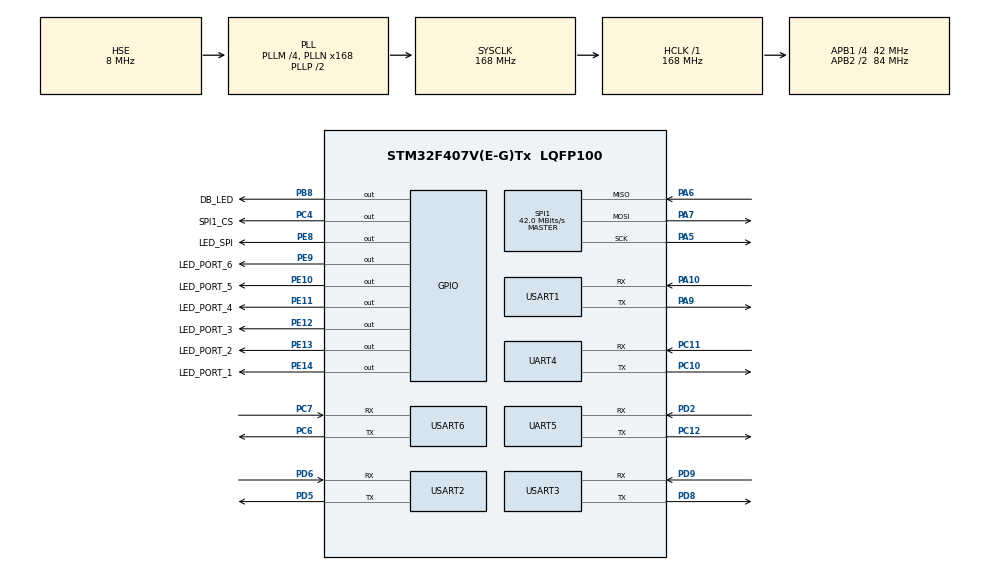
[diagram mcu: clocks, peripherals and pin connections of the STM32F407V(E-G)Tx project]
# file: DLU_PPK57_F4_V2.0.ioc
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Dma.Request0=SPI1_TX
Dma.Request1=UART4_RX
Dma.Request2=UART5_RX
Dma.Request3=USART1_RX
Dma.Request4=USART2_RX
Dma.Request5=USART3_RX
Dma.Request6=USART6_RX
Dma.SPI1_TX.0.Direction=DMA_MEMORY_TO_PERIPH
Dma.SPI1_TX.0.FIFOMode=DMA_FIFOMODE_DISABLE
Dma.SPI1_TX.0.Instance=DMA2_Stream3
Dma.SPI1_TX.0.MemDataAlignment=DMA_MDATAALIGN_BYTE
Dma.SPI1_TX.0.MemInc=DMA_MINC_ENABLE
Dma.SPI1_TX.0.Mode=DMA_NORMAL
Dma.SPI1_TX.0.PeriphDataAlignment=DMA_PDATAALIGN_BYTE
Dma.SPI1_TX.0.PeriphInc=DMA_PINC_DISABLE
Dma.SPI1_TX.0.Priority=DMA_PRIORITY_HIGH
Dma.UART4_RX.1.Direction=DMA_PERIPH_TO_MEMORY
Dma.UART4_RX.1.FIFOMode=DMA_FIFOMODE_DISABLE
Dma.UART4_RX.1.Instance=DMA1_Stream2
Dma.UART4_RX.1.MemDataAlignment=DMA_MDATAALIGN_BYTE
Dma.UART4_RX.1.MemInc=DMA_MINC_ENABLE
Dma.UART4_RX.1.Mode=DMA_NORMAL
Dma.UART4_RX.1.PeriphDataAlignment=DMA_PDATAALIGN_BYTE
Dma.UART4_RX.1.PeriphInc=DMA_PINC_DISABLE
Dma.UART4_RX.1.Priority=DMA_PRIORITY_VERY_HIGH
Dma.UART5_RX.2.Direction=DMA_PERIPH_TO_MEMORY
Dma.UART5_RX.2.FIFOMode=DMA_FIFOMODE_DISABLE
Dma.UART5_RX.2.Instance=DMA1_Stream0
Dma.UART5_RX.2.MemDataAlignment=DMA_MDATAALIGN_BYTE
Dma.UART5_RX.2.MemInc=DMA_MINC_ENABLE
Dma.UART5_RX.2.Mode=DMA_NORMAL
Dma.UART5_RX.2.PeriphDataAlignment=DMA_PDATAALIGN_BYTE
Dma.UART5_RX.2.PeriphInc=DMA_PINC_DISABLE
Dma.UART5_RX.2.Priority=DMA_PRIORITY_VERY_HIGH
Dma.USART1_RX.3.Direction=DMA_PERIPH_TO_MEMORY
Dma.USART1_RX.3.FIFOMode=DMA_FIFOMODE_DISABLE
Dma.USART1_RX.3.Instance=DMA2_Stream2
Dma.USART1_RX.3.MemDataAlignment=DMA_MDATAALIGN_BYTE
Dma.USART1_RX.3.MemInc=DMA_MINC_ENABLE
Dma.USART1_RX.3.Mode=DMA_NORMAL
Dma.USART1_RX.3.PeriphDataAlignment=DMA_PDATAALIGN_BYTE
Dma.USART1_RX.3.PeriphInc=DMA_PINC_DISABLE
Dma.USART1_RX.3.Priority=DMA_PRIORITY_VERY_HIGH
Dma.USART2_RX.4.Direction=DMA_PERIPH_TO_MEMORY
Dma.USART2_RX.4.FIFOMode=DMA_FIFOMODE_DISABLE
Dma.USART2_RX.4.Instance=DMA1_Stream5
Dma.USART2_RX.4.MemDataAlignment=DMA_MDATAALIGN_BYTE
Dma.USART2_RX.4.MemInc=DMA_MINC_ENABLE
Dma.USART2_RX.4.Mode=DMA_NORMAL
Dma.USART2_RX.4.PeriphDataAlignment=DMA_PDATAALIGN_BYTE
Dma.USART2_RX.4.PeriphInc=DMA_PINC_DISABLE
Dma.USART2_RX.4.Priority=DMA_PRIORITY_VERY_HIGH
Dma.USART3_RX.5.Direction=DMA_PERIPH_TO_MEMORY
Dma.USART3_RX.5.FIFOMode=DMA_FIFOMODE_DISABLE
Dma.USART3_RX.5.Instance=DMA1_Stream1
Dma.USART3_RX.5.MemDataAlignment=DMA_MDATAALIGN_BYTE
Dma.USART3_RX.5.MemInc=DMA_MINC_ENABLE
Dma.USART3_RX.5.Mode=DMA_NORMAL
Dma.USART3_RX.5.PeriphDataAlignment=DMA_PDATAALIGN_BYTE
Dma.USART3_RX.5.PeriphInc=DMA_PINC_DISABLE
Dma.USART3_RX.5.Priority=DMA_PRIORITY_VERY_HIGH
Dma.USART6_RX.6.Direction=DMA_PERIPH_TO_MEMORY
Dma.USART6_RX.6.FIFOMode=DMA_FIFOMODE_DISABLE
Dma.USART6_RX.6.Instance=DMA2_Stream1
Dma.USART6_RX.6.MemDataAlignment=DMA_MDATAALIGN_BYTE
Dma.USART6_RX.6.MemInc=DMA_MINC_ENABLE
Dma.USART6_RX.6.Mode=DMA_NORMAL
Dma.USART6_RX.6.PeriphDataAlignment=DMA_PDATAALIGN_BYTE
Dma.USART6_RX.6.PeriphInc=DMA_PINC_DISABLE
Dma.USART6_RX.6.Priority=DMA_PRIORITY_VERY_HIGH
Mcu.Family=STM32F4
Mcu.Name=STM32F407V(E-G)Tx
Mcu.Package=LQFP100
NVIC.DMA1_Stream0_IRQn=true\:0\:0\:false\:false\:true\:false\:true\:true
NVIC.DMA1_Stream1_IRQn=true\:0\:0\:false\:false\:true\:false\:true\:true
NVIC.DMA1_Stream2_IRQn=true\:0\:0\:false\:false\:true\:false\:true\:true
NVIC.DMA1_Stream5_IRQn=true\:0\:0\:false\:false\:true\:false\:true\:true
NVIC.DMA2_Stream1_IRQn=true\:0\:0\:false\:false\:true\:false\:true\:true
NVIC.DMA2_Stream2_IRQn=true\:0\:0\:false\:false\:true\:false\:true\:true
NVIC.DMA2_Stream3_IRQn=true\:0\:0\:false\:false\:true\:false\:true\:true
NVIC.PriorityGroup=NVIC_PRIORITYGROUP_4
NVIC.UART4_IRQn=true\:0\:0\:false\:false\:true\:true\:true\:true
NVIC.UART5_IRQn=true\:0\:0\:false\:false\:true\:true\:true\:true
NVIC.USART1_IRQn=true\:0\:0\:false\:false\:true\:true\:true\:true
NVIC.USART2_IRQn=true\:0\:0\:false\:false\:true\:true\:true\:true
NVIC.USART3_IRQn=true\:0\:0\:false\:false\:true\:true\:true\:true
NVIC.USART6_IRQn=true\:0\:0\:false\:false\:true\:true\:true\:true
PA10.Mode=Asynchronous
PA10.Signal=USART1_RX
PA13.Mode=Serial_Wire
PA13.Signal=SYS_JTMS-SWDIO
PA14.Mode=Serial_Wire
PA14.Signal=SYS_JTCK-SWCLK
PA5.Mode=Full_Duplex_Master
PA5.Signal=SPI1_SCK
PA6.Mode=Full_Duplex_Master
PA6.Signal=SPI1_MISO
PA7.Mode=Full_Duplex_Master
PA7.Signal=SPI1_MOSI
PA9.Mode=Asynchronous
PA9.Signal=USART1_TX
PB8.GPIO_Label=DB_LED
PB8.GPIO_Speed=GPIO_SPEED_FREQ_VERY_HIGH
PB8.Signal=GPIO_Output
PC10.Mode=Asynchronous
PC10.Signal=UART4_TX
PC11.Mode=Asynchronous
PC11.Signal=UART4_RX
PC12.Mode=Asynchronous
PC12.Signal=UART5_TX
PC4.GPIO_Label=SPI1_CS
PC4.GPIO_Speed=GPIO_SPEED_FREQ_VERY_HIGH
PC4.Signal=GPIO_Output
PC6.Mode=Asynchronous
PC6.Signal=USART6_TX
PC7.Mode=Asynchronous
PC7.Signal=USART6_RX
PD2.Mode=Asynchronous
PD2.Signal=UART5_RX
PD5.Mode=Asynchronous
PD5.Signal=USART2_TX
PD6.Mode=Asynchronous
PD6.Signal=USART2_RX
PD8.Mode=Asynchronous
PD8.Signal=USART3_TX
PD9.Mode=Asynchronous
PD9.Signal=USART3_RX
PE10.GPIO_Label=LED_PORT_5
PE10.GPIO_Speed=GPIO_SPEED_FREQ_VERY_HIGH
PE10.Signal=GPIO_Output
PE11.GPIO_Label=LED_PORT_4
PE11.GPIO_Speed=GPIO_SPEED_FREQ_VERY_HIGH
PE11.Signal=GPIO_Output
PE12.GPIO_Label=LED_PORT_3
PE12.GPIO_Speed=GPIO_SPEED_FREQ_VERY_HIGH
PE12.Signal=GPIO_Output
PE13.GPIO_Label=LED_PORT_2
PE13.GPIO_Speed=GPIO_SPEED_FREQ_VERY_HIGH
PE13.Signal=GPIO_Output
PE14.GPIO_Label=LED_PORT_1
PE14.GPIO_Speed=GPIO_SPEED_FREQ_VERY_HIGH
PE14.Signal=GPIO_Output
PE8.GPIO_Label=LED_SPI
PE8.GPIO_Speed=GPIO_SPEED_FREQ_VERY_HIGH
PE8.Signal=GPIO_Output
PE9.GPIO_Label=LED_PORT_6
PE9.GPIO_Speed=GPIO_SPEED_FREQ_VERY_HIGH
PE9.Signal=GPIO_Output
PH0-OSC_IN.Mode=HSE-External-Oscillator
PH0-OSC_IN.Signal=RCC_OSC_IN
PH1-OSC_OUT.Mode=HSE-External-Oscillator
PH1-OSC_OUT.Signal=RCC_OSC_OUT
ProjectManager.HeapSize=0x200
ProjectManager.StackSize=0x400
ProjectManager.TargetToolchain=STM32CubeIDE
RCC.48MHZClocksFreq_Value=84000000
RCC.AHBFreq_Value=168000000
RCC.APB1CLKDivider=RCC_HCLK_DIV4
RCC.APB1Freq_Value=42000000
RCC.APB1TimFreq_Value=84000000
RCC.APB2CLKDivider=RCC_HCLK_DIV2
RCC.APB2Freq_Value=84000000
RCC.APB2TimFreq_Value=168000000
RCC.CortexFreq_Value=168000000
RCC.HCLKFreq_Value=168000000
RCC.HSE_VALUE=8000000
RCC.HSI_VALUE=16000000
RCC.LSE_VALUE=32768
RCC.PLLM=4
RCC.PLLN=168
RCC.PLLSourceVirtual=RCC_PLLSOURCE_HSE
RCC.SYSCLKFreq_VALUE=168000000
RCC.SYSCLKSource=RCC_SYSCLKSOURCE_PLLCLK
RCC.VCOOutputFreq_Value=336000000
SPI1.CalculateBaudRate=42.0 MBits/s
SPI1.Direction=SPI_DIRECTION_2LINES
SPI1.Mode=SPI_MODE_MASTER
SPI1.VirtualType=VM_MASTER
UART4.VirtualMode=Asynchronous
UART5.VirtualMode=Asynchronous
USART1.VirtualMode=VM_ASYNC
USART2.VirtualMode=VM_ASYNC
USART3.VirtualMode=VM_ASYNC
USART6.VirtualMode=VM_ASYNC
board=custom

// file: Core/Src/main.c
/* USER CODE BEGIN Header */
/**
  ******************************************************************************
  * @file           : main.c
  * @brief          : Main program body
  ******************************************************************************
  * @attention
  *
  * Copyright (c) 2025 STMicroelectronics.
  * All rights reserved.
  *
  * This software is licensed under terms that can be found in the LICENSE file
  * in the root directory of this software component.
  * If no LICENSE file comes with this software, it is provided AS-IS.
  *
  ******************************************************************************
  */
/* USER CODE END Header */
#include "main.h"

SPI_HandleTypeDef hspi1;
DMA_HandleTypeDef hdma_spi1_tx;

UART_HandleTypeDef huart4;
UART_HandleTypeDef huart5;
UART_HandleTypeDef huart1;
UART_HandleTypeDef huart2;
UART_HandleTypeDef huart3;
UART_HandleTypeDef huart6;
DMA_HandleTypeDef hdma_uart4_rx;
DMA_HandleTypeDef hdma_uart5_rx;
DMA_HandleTypeDef hdma_usart1_rx;
DMA_HandleTypeDef hdma_usart2_rx;
DMA_HandleTypeDef hdma_usart3_rx;
DMA_HandleTypeDef hdma_usart6_rx;

void SystemClock_Config(void);
static void MX_GPIO_Init(void);
static void MX_DMA_Init(void);
static void MX_UART4_Init(void);
static void MX_UART5_Init(void);
static void MX_USART1_UART_Init(void);
static void MX_USART2_UART_Init(void);
static void MX_USART3_UART_Init(void);
static void MX_USART6_UART_Init(void);
static void MX_SPI1_Init(void);

int main(void)
{

  /* MCU Configuration--------------------------------------------------------*/

  /* Reset of all peripherals, Initializes the Flash interface and the Systick. */
  HAL_Init();

  /* Configure the system clock */
  SystemClock_Config();

  /* Initialize all configured peripherals */
  MX_GPIO_Init();
  MX_DMA_Init();
  MX_UART4_Init();
  MX_UART5_Init();
  MX_USART1_UART_Init();
  MX_USART2_UART_Init();
  MX_USART3_UART_Init();
  MX_USART6_UART_Init();
  MX_SPI1_Init();

  /* Infinite loop */
  while (1)
  {

  }
}

void SystemClock_Config(void)
{
  RCC_OscInitTypeDef RCC_OscInitStruct = {0};
  RCC_ClkInitTypeDef RCC_ClkInitStruct = {0};

  /** Configure the main internal regulator output voltage
  */
  __HAL_RCC_PWR_CLK_ENABLE();
  __HAL_PWR_VOLTAGESCALING_CONFIG(PWR_REGULATOR_VOLTAGE_SCALE1);

  /** Initializes the RCC Oscillators according to the specified parameters
  * in the RCC_OscInitTypeDef structure.
  */
  RCC_OscInitStruct.OscillatorType = RCC_OSCILLATORTYPE_HSE;
  RCC_OscInitStruct.HSEState = RCC_HSE_ON;
  RCC_OscInitStruct.PLL.PLLState = RCC_PLL_ON;
  RCC_OscInitStruct.PLL.PLLSource = RCC_PLLSOURCE_HSE;
  RCC_OscInitStruct.PLL.PLLM = 4;
  RCC_OscInitStruct.PLL.PLLN = 168;
  RCC_OscInitStruct.PLL.PLLP = RCC_PLLP_DIV2;
  RCC_OscInitStruct.PLL.PLLQ = 4;
  if (HAL_RCC_OscConfig(&RCC_OscInitStruct) != HAL_OK)
  {
    Error_Handler();
  }

  /** Initializes the CPU, AHB and APB buses clocks
  */
  RCC_ClkInitStruct.ClockType = RCC_CLOCKTYPE_HCLK|RCC_CLOCKTYPE_SYSCLK
                              |RCC_CLOCKTYPE_PCLK1|RCC_CLOCKTYPE_PCLK2;
  RCC_ClkInitStruct.SYSCLKSource = RCC_SYSCLKSOURCE_PLLCLK;
  RCC_ClkInitStruct.AHBCLKDivider = RCC_SYSCLK_DIV1;
  RCC_ClkInitStruct.APB1CLKDivider = RCC_HCLK_DIV4;
  RCC_ClkInitStruct.APB2CLKDivider = RCC_HCLK_DIV2;

  if (HAL_RCC_ClockConfig(&RCC_ClkInitStruct, FLASH_LATENCY_5) != HAL_OK)
  {
    Error_Handler();
  }
}

static void MX_SPI1_Init(void)
{

  /* SPI1 parameter configuration*/
  hspi1.Instance = SPI1;
  hspi1.Init.Mode = SPI_MODE_MASTER;
  hspi1.Init.Direction = SPI_DIRECTION_2LINES;
  hspi1.Init.DataSize = SPI_DATASIZE_8BIT;
  hspi1.Init.CLKPolarity = SPI_POLARITY_LOW;
  hspi1.Init.CLKPhase = SPI_PHASE_1EDGE;
  hspi1.Init.NSS = SPI_NSS_SOFT;
  hspi1.Init.BaudRatePrescaler = SPI_BAUDRATEPRESCALER_2;
  hspi1.Init.FirstBit = SPI_FIRSTBIT_MSB;
  hspi1.Init.TIMode = SPI_TIMODE_DISABLE;
  hspi1.Init.CRCCalculation = SPI_CRCCALCULATION_DISABLE;
  hspi1.Init.CRCPolynomial = 10;
  if (HAL_SPI_Init(&hspi1) != HAL_OK)
  {
    Error_Handler();
  }

}

static void MX_UART4_Init(void)
{

  huart4.Instance = UART4;
  huart4.Init.BaudRate = 115200;
  huart4.Init.WordLength = UART_WORDLENGTH_8B;
  huart4.Init.StopBits = UART_STOPBITS_1;
  huart4.Init.Parity = UART_PARITY_NONE;
  huart4.Init.Mode = UART_MODE_TX_RX;
  huart4.Init.HwFlowCtl = UART_HWCONTROL_NONE;
  huart4.Init.OverSampling = UART_OVERSAMPLING_16;
  if (HAL_UART_Init(&huart4) != HAL_OK)
  {
    Error_Handler();
  }

}

static void MX_UART5_Init(void)
{

  huart5.Instance = UART5;
  huart5.Init.BaudRate = 115200;
  huart5.Init.WordLength = UART_WORDLENGTH_8B;
  huart5.Init.StopBits = UART_STOPBITS_1;
  huart5.Init.Parity = UART_PARITY_NONE;
  huart5.Init.Mode = UART_MODE_TX_RX;
  huart5.Init.HwFlowCtl = UART_HWCONTROL_NONE;
  huart5.Init.OverSampling = UART_OVERSAMPLING_16;
  if (HAL_UART_Init(&huart5) != HAL_OK)
  {
    Error_Handler();
  }

}

static void MX_USART1_UART_Init(void)
{

  huart1.Instance = USART1;
  huart1.Init.BaudRate = 115200;
  huart1.Init.WordLength = UART_WORDLENGTH_8B;
  huart1.Init.StopBits = UART_STOPBITS_1;
  huart1.Init.Parity = UART_PARITY_NONE;
  huart1.Init.Mode = UART_MODE_TX_RX;
  huart1.Init.HwFlowCtl = UART_HWCONTROL_NONE;
  huart1.Init.OverSampling = UART_OVERSAMPLING_16;
  if (HAL_UART_Init(&huart1) != HAL_OK)
  {
    Error_Handler();
  }

}

static void MX_USART2_UART_Init(void)
{

  huart2.Instance = USART2;
  huart2.Init.BaudRate = 115200;
  huart2.Init.WordLength = UART_WORDLENGTH_8B;
  huart2.Init.StopBits = UART_STOPBITS_1;
  huart2.Init.Parity = UART_PARITY_NONE;
  huart2.Init.Mode = UART_MODE_TX_RX;
  huart2.Init.HwFlowCtl = UART_HWCONTROL_NONE;
  huart2.Init.OverSampling = UART_OVERSAMPLING_16;
  if (HAL_UART_Init(&huart2) != HAL_OK)
  {
    Error_Handler();
  }

}

static void MX_USART3_UART_Init(void)
{

  huart3.Instance = USART3;
  huart3.Init.BaudRate = 115200;
  huart3.Init.WordLength = UART_WORDLENGTH_8B;
  huart3.Init.StopBits = UART_STOPBITS_1;
  huart3.Init.Parity = UART_PARITY_NONE;
  huart3.Init.Mode = UART_MODE_TX_RX;
  huart3.Init.HwFlowCtl = UART_HWCONTROL_NONE;
  huart3.Init.OverSampling = UART_OVERSAMPLING_16;
  if (HAL_UART_Init(&huart3) != HAL_OK)
  {
    Error_Handler();
  }

}

static void MX_USART6_UART_Init(void)
{

  huart6.Instance = USART6;
  huart6.Init.BaudRate = 115200;
  huart6.Init.WordLength = UART_WORDLENGTH_8B;
  huart6.Init.StopBits = UART_STOPBITS_1;
  huart6.Init.Parity = UART_PARITY_NONE;
  huart6.Init.Mode = UART_MODE_TX_RX;
  huart6.Init.HwFlowCtl = UART_HWCONTROL_NONE;
  huart6.Init.OverSampling = UART_OVERSAMPLING_16;
  if (HAL_UART_Init(&huart6) != HAL_OK)
  {
    Error_Handler();
  }

}

static void MX_DMA_Init(void)
{

  /* DMA controller clock enable */
  __HAL_RCC_DMA2_CLK_ENABLE();
  __HAL_RCC_DMA1_CLK_ENABLE();

  /* DMA interrupt init */
  /* DMA1_Stream0_IRQn interrupt configuration */
  HAL_NVIC_SetPriority(DMA1_Stream0_IRQn, 0, 0);
  HAL_NVIC_EnableIRQ(DMA1_Stream0_IRQn);
  /* DMA1_Stream1_IRQn interrupt configuration */
  HAL_NVIC_SetPriority(DMA1_Stream1_IRQn, 0, 0);
  HAL_NVIC_EnableIRQ(DMA1_Stream1_IRQn);
  /* DMA1_Stream2_IRQn interrupt configuration */
  HAL_NVIC_SetPriority(DMA1_Stream2_IRQn, 0, 0);
  HAL_NVIC_EnableIRQ(DMA1_Stream2_IRQn);
  /* DMA1_Stream5_IRQn interrupt configuration */
  HAL_NVIC_SetPriority(DMA1_Stream5_IRQn, 0, 0);
  HAL_NVIC_EnableIRQ(DMA1_Stream5_IRQn);
  /* DMA2_Stream1_IRQn interrupt configuration */
  HAL_NVIC_SetPriority(DMA2_Stream1_IRQn, 0, 0);
  HAL_NVIC_EnableIRQ(DMA2_Stream1_IRQn);
  /* DMA2_Stream2_IRQn interrupt configuration */
  HAL_NVIC_SetPriority(DMA2_Stream2_IRQn, 0, 0);
  HAL_NVIC_EnableIRQ(DMA2_Stream2_IRQn);
  /* DMA2_Stream3_IRQn interrupt configuration */
  HAL_NVIC_SetPriority(DMA2_Stream3_IRQn, 0, 0);
  HAL_NVIC_EnableIRQ(DMA2_Stream3_IRQn);

}

static void MX_GPIO_Init(void)
{
  GPIO_InitTypeDef GPIO_InitStruct = {0};

  /* GPIO Ports Clock Enable */
  __HAL_RCC_GPIOH_CLK_ENABLE();
  __HAL_RCC_GPIOA_CLK_ENABLE();
  __HAL_RCC_GPIOC_CLK_ENABLE();
  __HAL_RCC_GPIOE_CLK_ENABLE();
  __HAL_RCC_GPIOD_CLK_ENABLE();
  __HAL_RCC_GPIOB_CLK_ENABLE();

  /*Configure GPIO pin Output Level */
  HAL_GPIO_WritePin(SPI1_CS_GPIO_Port, SPI1_CS_Pin, GPIO_PIN_RESET);

  /*Configure GPIO pin Output Level */
  HAL_GPIO_WritePin(GPIOE, LED_7_Pin|LED_6_Pin|LED_5_Pin|LED_4_Pin
                          |LED_3_Pin|LED_2_Pin|LED_1_Pin, GPIO_PIN_RESET);

  /*Configure GPIO pin Output Level */
  HAL_GPIO_WritePin(DB_LED_GPIO_Port, DB_LED_Pin, GPIO_PIN_RESET);

  /*Configure GPIO pin : SPI1_CS_Pin */
  GPIO_InitStruct.Pin = SPI1_CS_Pin;
  GPIO_InitStruct.Mode = GPIO_MODE_OUTPUT_PP;
  GPIO_InitStruct.Pull = GPIO_NOPULL;
  GPIO_InitStruct.Speed = GPIO_SPEED_FREQ_VERY_HIGH;
  HAL_GPIO_Init(SPI1_CS_GPIO_Port, &GPIO_InitStruct);

  /*Configure GPIO pins : LED_7_Pin LED_6_Pin LED_5_Pin LED_4_Pin
                           LED_3_Pin LED_2_Pin LED_1_Pin */
  GPIO_InitStruct.Pin = LED_7_Pin|LED_6_Pin|LED_5_Pin|LED_4_Pin
                          |LED_3_Pin|LED_2_Pin|LED_1_Pin;
  GPIO_InitStruct.Mode = GPIO_MODE_OUTPUT_PP;
  GPIO_InitStruct.Pull = GPIO_NOPULL;
  GPIO_InitStruct.Speed = GPIO_SPEED_FREQ_VERY_HIGH;
  HAL_GPIO_Init(GPIOE, &GPIO_InitStruct);

  /*Configure GPIO pin : DB_LED_Pin */
  GPIO_InitStruct.Pin = DB_LED_Pin;
  GPIO_InitStruct.Mode = GPIO_MODE_OUTPUT_PP;
  GPIO_InitStruct.Pull = GPIO_NOPULL;
  GPIO_InitStruct.Speed = GPIO_SPEED_FREQ_VERY_HIGH;
  HAL_GPIO_Init(DB_LED_GPIO_Port, &GPIO_InitStruct);

}

void Error_Handler(void)
{
  __disable_irq();
  while (1)
  {
  }
}
